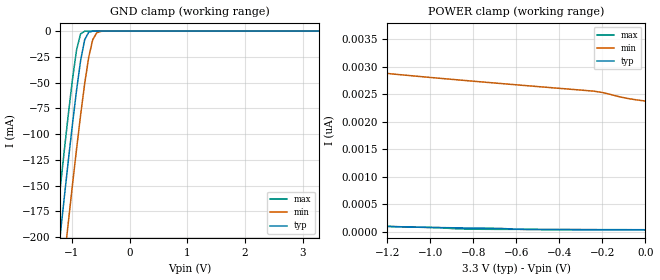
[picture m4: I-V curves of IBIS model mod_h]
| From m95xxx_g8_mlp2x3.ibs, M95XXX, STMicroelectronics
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|   Model mod_h
[Model]   mod_h
Model_type Input
Vinl   =   1.000V
Vinh   =   2.300V
C_comp   2.120pF   2.024pF   2.323pF
[Temperature Range]  25.0000   0.1050k   -40.0000
[Voltage Range]   3.3000V   2.7000V   3.6000V
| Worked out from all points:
|   GND clamp passes 1 mA (typ) near -0.70 V on its own axis
[GND_clamp]
|Voltage   I(typ)   I(min)   I(max)
-3.3V     -1.355A    -1.412A    -1.313A
-1.34V    -270.3mA   -330.7mA   -224.8mA
-1.27V    -233mA     -293.4mA   -187.4mA
-1.2V     -196.1mA   -256.5mA   -150.5mA
-1.13V    -159.7mA   -219.9mA   -114.2mA
-1.06V    -124.1mA   -183.9mA   -79.16mA
-920mV    -57.12mA   -114.2mA   -18.15mA
-850mV    -28.51mA   -81.35mA   -2.609mA
-780mV    -8.357mA   -51.08mA   -131.1uA
-640mV    -95.71uA   -8.329mA   -224.5nA
-500mV    -655.8nA   -243.4uA   -381.5pA
3.28V     6.871pA    315.5pA    6.69pA
[POWER_clamp]
|Voltage   I(typ)   I(min)   I(max)
-3.28V    711.2nA    13.65nA    1.989uA
-2.64V    3.971nA    4.228nA    202nA
-2.56V    2.606nA    4.045nA    79.07nA
-2.52V    2.267nA    3.964nA    43.04nA
-2.36V    1.394nA    3.694nA    3.8nA
-2.32V    1.239nA    3.636nA    2.862nA
-2.28V    1.102nA    3.582nA    2.361nA
-2.2V     874.7pA    3.484nA    1.719nA
-2.08V    623.6pA    3.363nA    1.095nA
-1.92V    405.5pA    3.236nA    613.9pA
-1.4V     130.7pA    2.959nA    136.6pA
0V        33.08pA    2.378nA    36.22pA
